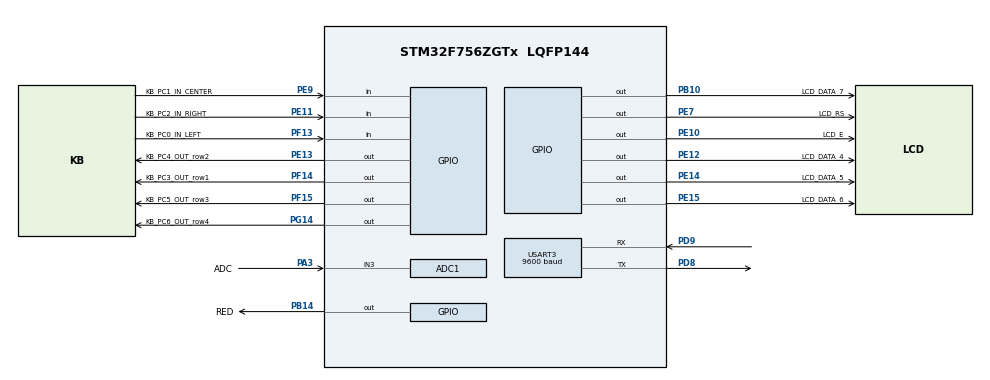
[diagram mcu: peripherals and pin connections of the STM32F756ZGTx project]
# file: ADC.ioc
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ADC1.Channel-0\#ChannelRegularConversion=ADC_CHANNEL_3
ADC1.NbrOfConversionFlag=1
ADC1.Rank-0\#ChannelRegularConversion=1
ADC1.SamplingTime-0\#ChannelRegularConversion=ADC_SAMPLETIME_3CYCLES
ADC1.master=1
Mcu.Family=STM32F7
Mcu.Name=STM32F756ZGTx
Mcu.Package=LQFP144
NVIC.ADC_IRQn=true\:0\:0\:false\:false\:true\:true\:true
NVIC.PriorityGroup=NVIC_PRIORITYGROUP_4
NVIC.TIM8_TRG_COM_TIM14_IRQn=true\:0\:0\:false\:false\:true\:true\:true
NVIC.USART3_IRQn=true\:0\:0\:false\:false\:true\:true\:true
PA3.GPIO_Label=ADC
PA3.Signal=ADCx_IN3
PB10.GPIO_Label=LCD_DATA_7
PB10.Signal=GPIO_Output
PB14.GPIO_Label=RED
PB14.Signal=GPIO_Output
PD8.Mode=Asynchronous
PD8.Signal=USART3_TX
PD9.Mode=Asynchronous
PD9.Signal=USART3_RX
PE10.GPIO_Label=LCD_E
PE10.Signal=GPIO_Output
PE11.GPIO_Label=KB_PC2_IN_RIGHT
PE11.Signal=GPIO_Input
PE12.GPIO_Label=LCD_DATA_4
PE12.Signal=GPIO_Output
PE13.GPIO_Label=KB_PC4_OUT_row2
PE13.Signal=GPIO_Output
PE14.GPIO_Label=LCD_DATA_5
PE14.Signal=GPIO_Output
PE15.GPIO_Label=LCD_DATA_6
PE15.Signal=GPIO_Output
PE7.GPIO_Label=LCD_RS
PE7.Signal=GPIO_Output
PE9.GPIO_Label=KB_PC1_IN_CENTER
PE9.Signal=GPIO_Input
PF13.GPIO_Label=KB_PC0_IN_LEFT
PF13.Signal=GPIO_Input
PF14.GPIO_Label=KB_PC3_OUT_row1
PF14.Signal=GPIO_Output
PF15.GPIO_Label=KB_PC5_OUT_row3
PF15.Signal=GPIO_Output
PG14.GPIO_Label=KB_PC6_OUT_row4
PG14.Signal=GPIO_Output
ProjectManager.HeapSize=0x200
ProjectManager.StackSize=0x400
ProjectManager.TargetToolchain=STM32CubeIDE
RCC.HSE_VALUE=25000000
RCC.HSI_VALUE=16000000
RCC.LSE_VALUE=32768
RCC.USBFreq_Value=96000000
RCC.VCOOutputFreq_Value=192000000
SH.ADCx_IN3.0=ADC1_IN3,IN3
TIM14.Prescaler=48
USART3.BaudRate=9600
USART3.VirtualMode-Asynchronous=VM_ASYNC
VP_TIM14_VS_ClockSourceINT.Mode=Enable_Timer
board=custom

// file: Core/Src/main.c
/* USER CODE BEGIN Header */
/**
  ******************************************************************************
  * @file           : main.c
  * @brief          : Main program body
  ******************************************************************************
  * @attention
  *
  * <h2><center>&copy; Copyright (c) 2021 STMicroelectronics.
  * All rights reserved.</center></h2>
  *
  * This software component is licensed by ST under BSD 3-Clause license,
  * the "License"; You may not use this file except in compliance with the
  * License. You may obtain a copy of the License at:
  *                        opensource.org/licenses/BSD-3-Clause
  *
  ******************************************************************************
  */
/* USER CODE END Header */
#include "main.h"

/* USER CODE BEGIN Includes */
#include "lcd.h"
#include <String.h>
/* USER CODE END Includes */

ADC_HandleTypeDef hadc1;

TIM_HandleTypeDef htim14;

UART_HandleTypeDef huart3;

uint16_t fesz = 0;

char adc_ki[5];
uint8_t write = 0;

void SystemClock_Config(void);
static void MX_GPIO_Init(void);
static void MX_ADC1_Init(void);
static void MX_USART3_UART_Init(void);
static void MX_TIM14_Init(void);
/* USER CODE BEGIN PFP */

void HAL_TIM_PeriodElapsedCallback (TIM_HandleTypeDef * htim)
{

		HAL_ADC_Start(&hadc1);
		uint16_t adc =  HAL_ADC_GetValue(&hadc1);
		fesz = (3300*adc)/4096;
		HAL_GPIO_TogglePin(RED_GPIO_Port, RED_Pin);
}

/* USER CODE END PFP */

int main(void)
{

  /* MCU Configuration--------------------------------------------------------*/

  /* Reset of all peripherals, Initializes the Flash interface and the Systick. */
  HAL_Init();

  /* Configure the system clock */
  SystemClock_Config();

  /* Initialize all configured peripherals */
  MX_GPIO_Init();
  MX_ADC1_Init();
  MX_USART3_UART_Init();
  MX_TIM14_Init();
  /* USER CODE BEGIN 2 */
  LCD_init();
  LCD_cmd(0x01);
  LCD_cmd(0x80);
  HAL_TIM_Base_Start_IT(&htim14);
  /* USER CODE END 2 */

  /* Infinite loop */
  /* USER CODE BEGIN WHILE */
  while (1)
  {
	  LCD_xy(0,1);
	  if(fesz >= 0 && fesz <= 500)
	  {
		  	 LCD_xy(15,4);
		  	 LCD_string(" ");
		  	 LCD_xy(15,3);
		  	 LCD_string(" ");
			 LCD_xy(15,2);
			 LCD_string(" ");
			 LCD_xy(15,1);
			 LCD_string(" ");
	  }
	  else
	  {
	  	if(fesz >= 501 && fesz <= 1000)
	  	{
		  	 LCD_xy(15,4);
		  	 LCD_string("*");
		  	 LCD_xy(15,3);
		  	 LCD_string(" ");
			 LCD_xy(15,2);
			 LCD_string(" ");
			 LCD_xy(15,1);
			 LCD_string(" ");
	  	}
	  	else
	  	{
	  		if(fesz >= 1001 && fesz <= 2000)
	  		{
			  	 LCD_xy(15,4);
			  	 LCD_string("*");
			  	 LCD_xy(15,3);
			  	 LCD_string("*");
				 LCD_xy(15,2);
				 LCD_string(" ");
				 LCD_xy(15,1);
				 LCD_string(" ");
	  		}
	  		else
	  		{
	  			if(fesz >= 2001 && fesz <= 3000)
	  			{
	  			  	 LCD_xy(15,4);
	  			  	 LCD_string("*");
	  			  	 LCD_xy(15,3);
	  			  	 LCD_string("*");
	  				 LCD_xy(15,2);
	  				 LCD_string("*");
	  				 LCD_xy(15,1);
	  				 LCD_string(" ");
	  			}
	  			else
	  			{
	  			  	 LCD_xy(15,4);
	  			  	 LCD_string("*");
	  			  	 LCD_xy(15,3);
	  			  	 LCD_string("*");
	  				 LCD_xy(15,2);
	  				 LCD_string("*");
	  				 LCD_xy(15,1);
	  				 LCD_string("*");
	  			}
	  	}
	  		}
	  }
	  char uart[6];
	  sprintf(uart,"%d\n\r",fesz);
	  HAL_UART_Transmit(&huart3, (uint8_t*) uart, sizeof(uart), HAL_MAX_DELAY);

    /* USER CODE END WHILE */

  }
}

void SystemClock_Config(void)
{
  RCC_OscInitTypeDef RCC_OscInitStruct = {0};
  RCC_ClkInitTypeDef RCC_ClkInitStruct = {0};
  RCC_PeriphCLKInitTypeDef PeriphClkInitStruct = {0};

  /** Configure the main internal regulator output voltage
  */
  __HAL_RCC_PWR_CLK_ENABLE();
  __HAL_PWR_VOLTAGESCALING_CONFIG(PWR_REGULATOR_VOLTAGE_SCALE3);
  /** Initializes the RCC Oscillators according to the specified parameters
  * in the RCC_OscInitTypeDef structure.
  */
  RCC_OscInitStruct.OscillatorType = RCC_OSCILLATORTYPE_HSI;
  RCC_OscInitStruct.HSIState = RCC_HSI_ON;
  RCC_OscInitStruct.HSICalibrationValue = RCC_HSICALIBRATION_DEFAULT;
  RCC_OscInitStruct.PLL.PLLState = RCC_PLL_NONE;
  if (HAL_RCC_OscConfig(&RCC_OscInitStruct) != HAL_OK)
  {
    Error_Handler();
  }
  /** Initializes the CPU, AHB and APB buses clocks
  */
  RCC_ClkInitStruct.ClockType = RCC_CLOCKTYPE_HCLK|RCC_CLOCKTYPE_SYSCLK
                              |RCC_CLOCKTYPE_PCLK1|RCC_CLOCKTYPE_PCLK2;
  RCC_ClkInitStruct.SYSCLKSource = RCC_SYSCLKSOURCE_HSI;
  RCC_ClkInitStruct.AHBCLKDivider = RCC_SYSCLK_DIV1;
  RCC_ClkInitStruct.APB1CLKDivider = RCC_HCLK_DIV1;
  RCC_ClkInitStruct.APB2CLKDivider = RCC_HCLK_DIV1;

  if (HAL_RCC_ClockConfig(&RCC_ClkInitStruct, FLASH_LATENCY_0) != HAL_OK)
  {
    Error_Handler();
  }
  PeriphClkInitStruct.PeriphClockSelection = RCC_PERIPHCLK_USART3;
  PeriphClkInitStruct.Usart3ClockSelection = RCC_USART3CLKSOURCE_PCLK1;
  if (HAL_RCCEx_PeriphCLKConfig(&PeriphClkInitStruct) != HAL_OK)
  {
    Error_Handler();
  }
}

static void MX_ADC1_Init(void)
{

  ADC_ChannelConfTypeDef sConfig = {0};

  /** Configure the global features of the ADC (Clock, Resolution, Data Alignment and number of conversion)
  */
  hadc1.Instance = ADC1;
  hadc1.Init.ClockPrescaler = ADC_CLOCK_SYNC_PCLK_DIV2;
  hadc1.Init.Resolution = ADC_RESOLUTION_12B;
  hadc1.Init.ScanConvMode = ADC_SCAN_DISABLE;
  hadc1.Init.ContinuousConvMode = DISABLE;
  hadc1.Init.DiscontinuousConvMode = DISABLE;
  hadc1.Init.ExternalTrigConvEdge = ADC_EXTERNALTRIGCONVEDGE_NONE;
  hadc1.Init.ExternalTrigConv = ADC_SOFTWARE_START;
  hadc1.Init.DataAlign = ADC_DATAALIGN_RIGHT;
  hadc1.Init.NbrOfConversion = 1;
  hadc1.Init.DMAContinuousRequests = DISABLE;
  hadc1.Init.EOCSelection = ADC_EOC_SINGLE_CONV;
  if (HAL_ADC_Init(&hadc1) != HAL_OK)
  {
    Error_Handler();
  }
  /** Configure for the selected ADC regular channel its corresponding rank in the sequencer and its sample time.
  */
  sConfig.Channel = ADC_CHANNEL_3;
  sConfig.Rank = ADC_REGULAR_RANK_1;
  sConfig.SamplingTime = ADC_SAMPLETIME_3CYCLES;
  if (HAL_ADC_ConfigChannel(&hadc1, &sConfig) != HAL_OK)
  {
    Error_Handler();
  }

}

static void MX_TIM14_Init(void)
{

  htim14.Instance = TIM14;
  htim14.Init.Prescaler = 48;
  htim14.Init.CounterMode = TIM_COUNTERMODE_UP;
  htim14.Init.Period = 65535;
  htim14.Init.ClockDivision = TIM_CLOCKDIVISION_DIV1;
  htim14.Init.AutoReloadPreload = TIM_AUTORELOAD_PRELOAD_DISABLE;
  if (HAL_TIM_Base_Init(&htim14) != HAL_OK)
  {
    Error_Handler();
  }

}

static void MX_USART3_UART_Init(void)
{

  huart3.Instance = USART3;
  huart3.Init.BaudRate = 9600;
  huart3.Init.WordLength = UART_WORDLENGTH_8B;
  huart3.Init.StopBits = UART_STOPBITS_1;
  huart3.Init.Parity = UART_PARITY_NONE;
  huart3.Init.Mode = UART_MODE_TX_RX;
  huart3.Init.HwFlowCtl = UART_HWCONTROL_NONE;
  huart3.Init.OverSampling = UART_OVERSAMPLING_16;
  huart3.Init.OneBitSampling = UART_ONE_BIT_SAMPLE_DISABLE;
  huart3.AdvancedInit.AdvFeatureInit = UART_ADVFEATURE_NO_INIT;
  if (HAL_UART_Init(&huart3) != HAL_OK)
  {
    Error_Handler();
  }

}

static void MX_GPIO_Init(void)
{
  GPIO_InitTypeDef GPIO_InitStruct = {0};

  /* GPIO Ports Clock Enable */
  __HAL_RCC_GPIOA_CLK_ENABLE();
  __HAL_RCC_GPIOB_CLK_ENABLE();
  __HAL_RCC_GPIOF_CLK_ENABLE();
  __HAL_RCC_GPIOE_CLK_ENABLE();
  __HAL_RCC_GPIOD_CLK_ENABLE();
  __HAL_RCC_GPIOG_CLK_ENABLE();

  /*Configure GPIO pin Output Level */
  HAL_GPIO_WritePin(GPIOF, KB_PC3_OUT_row1_Pin|KB_PC5_OUT_row3_Pin, GPIO_PIN_RESET);

  /*Configure GPIO pin Output Level */
  HAL_GPIO_WritePin(GPIOE, LCD_RS_Pin|LCD_E_Pin|LCD_DATA_4_Pin|KB_PC4_OUT_row2_Pin
                          |LCD_DATA_5_Pin|LCD_DATA_6_Pin, GPIO_PIN_RESET);

  /*Configure GPIO pin Output Level */
  HAL_GPIO_WritePin(GPIOB, LCD_DATA_7_Pin|RED_Pin, GPIO_PIN_RESET);

  /*Configure GPIO pin Output Level */
  HAL_GPIO_WritePin(KB_PC6_OUT_row4_GPIO_Port, KB_PC6_OUT_row4_Pin, GPIO_PIN_RESET);

  /*Configure GPIO pin : PB0 */
  GPIO_InitStruct.Pin = GPIO_PIN_0;
  GPIO_InitStruct.Mode = GPIO_MODE_AF_PP;
  GPIO_InitStruct.Pull = GPIO_NOPULL;
  GPIO_InitStruct.Speed = GPIO_SPEED_FREQ_LOW;
  GPIO_InitStruct.Alternate = GPIO_AF2_TIM3;
  HAL_GPIO_Init(GPIOB, &GPIO_InitStruct);

  /*Configure GPIO pin : KB_PC0_IN_LEFT_Pin */
  GPIO_InitStruct.Pin = KB_PC0_IN_LEFT_Pin;
  GPIO_InitStruct.Mode = GPIO_MODE_INPUT;
  GPIO_InitStruct.Pull = GPIO_NOPULL;
  HAL_GPIO_Init(KB_PC0_IN_LEFT_GPIO_Port, &GPIO_InitStruct);

  /*Configure GPIO pins : KB_PC3_OUT_row1_Pin KB_PC5_OUT_row3_Pin */
  GPIO_InitStruct.Pin = KB_PC3_OUT_row1_Pin|KB_PC5_OUT_row3_Pin;
  GPIO_InitStruct.Mode = GPIO_MODE_OUTPUT_PP;
  GPIO_InitStruct.Pull = GPIO_NOPULL;
  GPIO_InitStruct.Speed = GPIO_SPEED_FREQ_LOW;
  HAL_GPIO_Init(GPIOF, &GPIO_InitStruct);

  /*Configure GPIO pins : LCD_RS_Pin LCD_E_Pin LCD_DATA_4_Pin KB_PC4_OUT_row2_Pin
                           LCD_DATA_5_Pin LCD_DATA_6_Pin */
  GPIO_InitStruct.Pin = LCD_RS_Pin|LCD_E_Pin|LCD_DATA_4_Pin|KB_PC4_OUT_row2_Pin
                          |LCD_DATA_5_Pin|LCD_DATA_6_Pin;
  GPIO_InitStruct.Mode = GPIO_MODE_OUTPUT_PP;
  GPIO_InitStruct.Pull = GPIO_NOPULL;
  GPIO_InitStruct.Speed = GPIO_SPEED_FREQ_LOW;
  HAL_GPIO_Init(GPIOE, &GPIO_InitStruct);

  /*Configure GPIO pins : KB_PC1_IN_CENTER_Pin KB_PC2_IN_RIGHT_Pin */
  GPIO_InitStruct.Pin = KB_PC1_IN_CENTER_Pin|KB_PC2_IN_RIGHT_Pin;
  GPIO_InitStruct.Mode = GPIO_MODE_INPUT;
  GPIO_InitStruct.Pull = GPIO_NOPULL;
  HAL_GPIO_Init(GPIOE, &GPIO_InitStruct);

  /*Configure GPIO pins : LCD_DATA_7_Pin RED_Pin */
  GPIO_InitStruct.Pin = LCD_DATA_7_Pin|RED_Pin;
  GPIO_InitStruct.Mode = GPIO_MODE_OUTPUT_PP;
  GPIO_InitStruct.Pull = GPIO_NOPULL;
  GPIO_InitStruct.Speed = GPIO_SPEED_FREQ_LOW;
  HAL_GPIO_Init(GPIOB, &GPIO_InitStruct);

  /*Configure GPIO pin : KB_PC6_OUT_row4_Pin */
  GPIO_InitStruct.Pin = KB_PC6_OUT_row4_Pin;
  GPIO_InitStruct.Mode = GPIO_MODE_OUTPUT_PP;
  GPIO_InitStruct.Pull = GPIO_NOPULL;
  GPIO_InitStruct.Speed = GPIO_SPEED_FREQ_LOW;
  HAL_GPIO_Init(KB_PC6_OUT_row4_GPIO_Port, &GPIO_InitStruct);

  /*Configure GPIO pin : PB7 */
  GPIO_InitStruct.Pin = GPIO_PIN_7;
  GPIO_InitStruct.Mode = GPIO_MODE_AF_PP;
  GPIO_InitStruct.Pull = GPIO_NOPULL;
  GPIO_InitStruct.Speed = GPIO_SPEED_FREQ_LOW;
  GPIO_InitStruct.Alternate = GPIO_AF2_TIM4;
  HAL_GPIO_Init(GPIOB, &GPIO_InitStruct);

}

void Error_Handler(void)
{
  __disable_irq();
  while (1)
  {
  }
}

/************************ (C) COPYRIGHT STMicroelectronics *****END OF FILE****/
